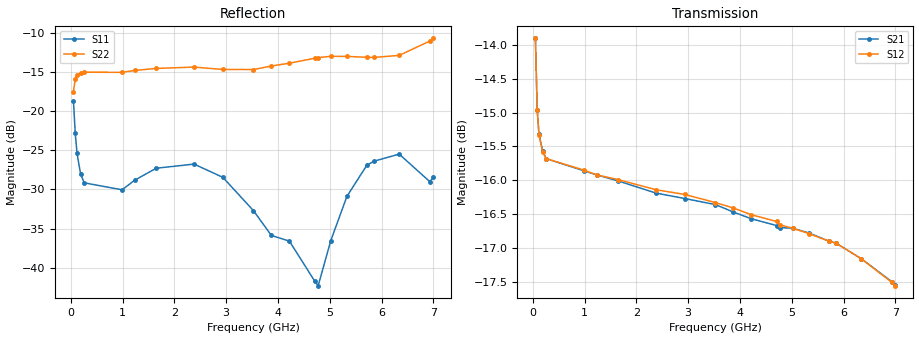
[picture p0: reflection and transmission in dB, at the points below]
! Integrated Device Technology
! Corporate Headquarters
! 6024 Silver Creek Valley Road
! San Jose, CA 95138  USA
! Phone:  1-408-284-8200
! Toll Free:  1-800-223-1366
! Webpage:  http://www.idt.com/
! Timing and RF Division
! 515 Groton Road, Suite 102
! Westford, MA 01886-6024
! Device:  F2258
! Description: Voltage Variable RF Attenuator
! Frequency:  50.0 -  6000.00 MHz
! Package:  3x3 mm Thin QFN Plastic Package: 16 pin
! Ports:  2 RF, 2 DC
!  Pin  1  = NC
!  Pin  2  = NC
!  Pin  3  = RF2  = Port 2
!  Pin  4  = GND
!  Pin  5  = Vdd
!  Pin  6  = NC
!  Pin  7  = VCTRL
!  Pin  8  = NC
!  Pin  9  = GND
!  Pin 10  = RF1  = Port 1
!  Pin 11  = NC
!  Pin 12  = NC
!  Pin 13  = NC
!  Pin 14  = NC
!  Pin 15  = NC
!  Pin 16  = NC
! Vcntrl:  1.200 Volts
! Vdd:  +3.300 Volts
! Current:  1.167 mA
! Data:  The device was measured on a the F2258 evaluation board which has
!  individual transmission lines to the RF pins.  Data was collected
!  using a calibrated network analyzer.  The evaluation board was
!  de-embedded using a TRL calibration technique.
!  The reference plane is the edge of the package pin.
! Misc:  SN 10
!  Action Tracker AT0285
! Date Measured:  2014-12-10
! Date:  2016-01-13  MJV
! Note:
!  Integrated Device Technology supplies this data as a sample of measured
!  data at the package pin for this product.  Your particular data for this
!  product may vary.
!  Data was taken at 25 degrees C.
!  Integrated Device Technology reserves the right to change this data at anytime.
!Freq_(GHz)  S11M_(dB)  S11P_(deg)  S21M_(dB)  S21P_(deg)  S12M_(dB)  S12P_(deg)  S22M_(dB)  S22P_(deg)
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# GHz S dB R 50
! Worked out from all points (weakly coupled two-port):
!   201 points, 50 MHz to 7 GHz, reference 50 ohm
!   highest |S21| = -13.90 dB at 50 MHz (marker M1); lowest = -17.5 dB at 7 GHz (marker M2)
!   lowest |S11| = -42.3 dB at 4.776 GHz (marker M3), VSWR 1.02, Z = 50.6 + j0.457 ohm
!   |S11| at or under -10 dB: start of sweep to end of sweep
!   |S22| runs from -17.5 to -10.7 dB; largest |S21 - S12| = 0.0014
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0.05  -18.66 -94.3  -13.90 -23.5  -13.90 -23.5  -17.49 -22.6
0.08475  -22.81 -80.0  -14.96 -16.8  -14.96 -16.8  -15.83 -11.9
0.1195  -25.38 -68.4  -15.32 -13.4  -15.33 -13.4  -15.36 -9.7
0.189  -28.05 -52.1  -15.57 -10.6  -15.58 -10.6  -15.07 -9.1
0.2585  -29.15 -40.3  -15.68 -9.8  -15.68 -9.8  -14.98 -9.9
0.98825  -30.04 -19.1  -15.86 -16.8  -15.85 -16.8  -15.00 -28.2
1.2315  -28.82 -14.6  -15.92 -20.2  -15.92 -20.2  -14.76 -34.1
1.6485  -27.28 -9.9  -16.01 -26.0  -15.99 -26.0  -14.50 -44.1
2.37825  -26.75 2.1  -16.19 -36.3  -16.14 -36.3  -14.33 -61.1
2.93425  -28.44 16.0  -16.27 -44.4  -16.21 -44.4  -14.63 -77.0
3.525  -32.70 41.5  -16.36 -53.1  -16.33 -53.1  -14.64 -98.8
3.8725  -35.89 68.8  -16.47 -58.2  -16.41 -58.2  -14.19 -111.7
4.22  -36.61 87.3  -16.57 -63.2  -16.51 -63.3  -13.83 -121.8
4.7065  -41.71 53.3  -16.67 -70.2  -16.61 -70.2  -13.20 -132.1
4.776  -42.32 36.2  -16.70 -71.2  -16.66 -71.2  -13.11 -133.2
5.01925  -36.55 1.1  -16.71 -74.6  -16.71 -74.7  -12.95 -136.7
5.332  -30.87 -8.9  -16.78 -79.0  -16.79 -79.0  -12.96 -140.5
5.71425  -26.91 -6.1  -16.90 -84.3  -16.90 -84.3  -13.07 -146.4
5.85325  -26.38 -3.3  -16.93 -86.3  -16.93 -86.3  -13.09 -149.5
6.33975  -25.47 10.0  -17.16 -93.1  -17.16 -93.1  -12.83 -161.7
6.9305  -28.99 72.7  -17.50 -100.4  -17.51 -100.4  -11.00 -178.8
7  -28.46 87.7  -17.55 -101.2  -17.56 -101.2  -10.65 179.1
